VERSION 5.7 ;
  NOWIREEXTENSIONATPIN ON ;
  DIVIDERCHAR "/" ;
  BUSBITCHARS "[]" ;
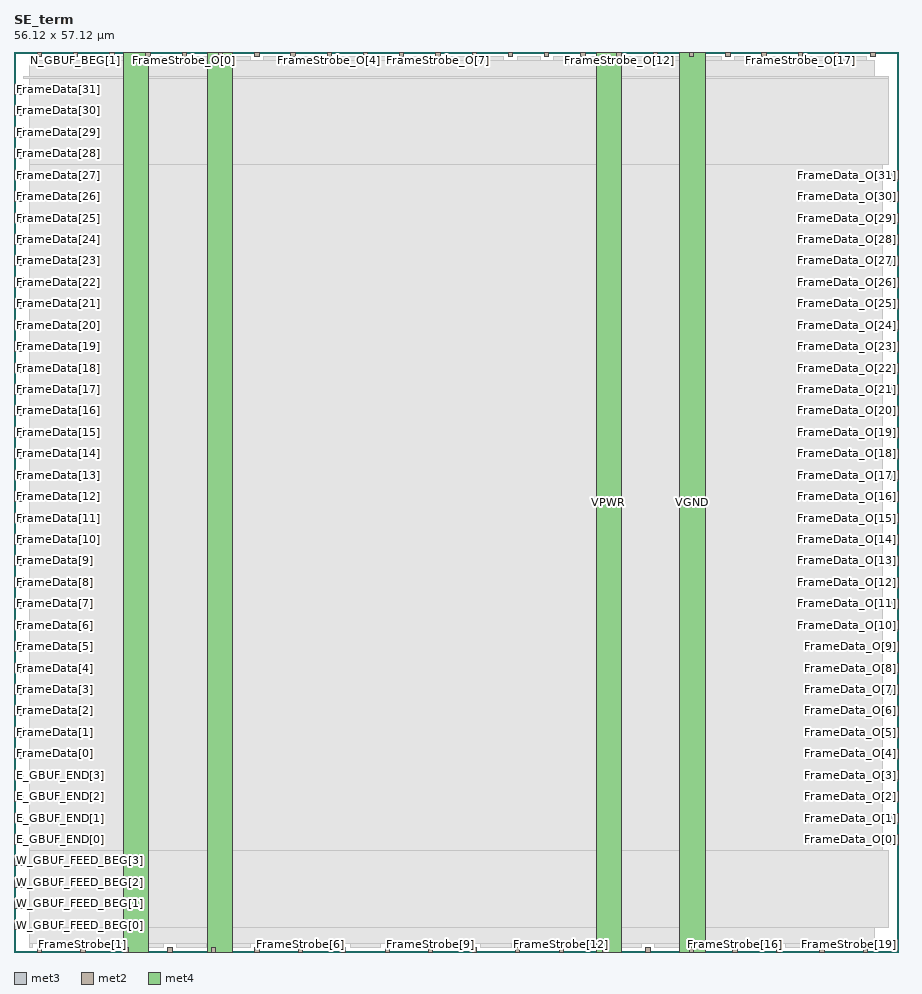
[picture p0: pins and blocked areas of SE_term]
MACRO SE_term
  CLASS BLOCK ;
  FOREIGN SE_term ;
  ORIGIN 0.000 0.000 ;
  SIZE 56.120 BY 57.120 ;
  PIN E_GBUF_END[0]
    DIRECTION INPUT ;
    USE SIGNAL ;
    ANTENNAGATEAREA 0.159000 ;
    PORT
      LAYER met3 ;
        RECT 0.000 6.840 0.600 7.440 ;
    END
  END E_GBUF_END[0]
  PIN E_GBUF_END[1]
    DIRECTION INPUT ;
    USE SIGNAL ;
    ANTENNAGATEAREA 0.159000 ;
    PORT
      LAYER met3 ;
        RECT 0.000 8.200 0.600 8.800 ;
    END
  END E_GBUF_END[1]
  PIN E_GBUF_END[2]
    DIRECTION INPUT ;
    USE SIGNAL ;
    ANTENNAGATEAREA 0.159000 ;
    PORT
      LAYER met3 ;
        RECT 0.000 9.560 0.600 10.160 ;
    END
  END E_GBUF_END[2]
  PIN E_GBUF_END[3]
    DIRECTION INPUT ;
    USE SIGNAL ;
    ANTENNAGATEAREA 0.159000 ;
    PORT
      LAYER met3 ;
        RECT 0.000 10.920 0.600 11.520 ;
    END
  END E_GBUF_END[3]
  PIN FrameData[0]
    DIRECTION INPUT ;
    USE SIGNAL ;
    ANTENNAGATEAREA 0.593700 ;
    ANTENNADIFFAREA 0.434700 ;
    PORT
      LAYER met3 ;
        RECT 0.000 12.280 0.600 12.880 ;
    END
  END FrameData[0]
  PIN FrameData[10]
    DIRECTION INPUT ;
    USE SIGNAL ;
    ANTENNAGATEAREA 0.159000 ;
    PORT
      LAYER met3 ;
        RECT 0.000 25.880 0.600 26.480 ;
    END
  END FrameData[10]
  PIN FrameData[11]
    DIRECTION INPUT ;
    USE SIGNAL ;
    ANTENNAGATEAREA 0.159000 ;
    PORT
      LAYER met3 ;
        RECT 0.000 27.240 0.600 27.840 ;
    END
  END FrameData[11]
  PIN FrameData[12]
    DIRECTION INPUT ;
    USE SIGNAL ;
    ANTENNAGATEAREA 0.159000 ;
    PORT
      LAYER met3 ;
        RECT 0.000 28.600 0.600 29.200 ;
    END
  END FrameData[12]
  PIN FrameData[13]
    DIRECTION INPUT ;
    USE SIGNAL ;
    ANTENNAGATEAREA 0.159000 ;
    PORT
      LAYER met3 ;
        RECT 0.000 29.960 0.600 30.560 ;
    END
  END FrameData[13]
  PIN FrameData[14]
    DIRECTION INPUT ;
    USE SIGNAL ;
    ANTENNAGATEAREA 0.159000 ;
    PORT
      LAYER met3 ;
        RECT 0.000 31.320 0.600 31.920 ;
    END
  END FrameData[14]
  PIN FrameData[15]
    DIRECTION INPUT ;
    USE SIGNAL ;
    ANTENNAGATEAREA 0.159000 ;
    PORT
      LAYER met3 ;
        RECT 0.000 32.680 0.600 33.280 ;
    END
  END FrameData[15]
  PIN FrameData[16]
    DIRECTION INPUT ;
    USE SIGNAL ;
    ANTENNAGATEAREA 0.159000 ;
    PORT
      LAYER met3 ;
        RECT 0.000 34.040 0.600 34.640 ;
    END
  END FrameData[16]
  PIN FrameData[17]
    DIRECTION INPUT ;
    USE SIGNAL ;
    ANTENNAGATEAREA 0.159000 ;
    PORT
      LAYER met3 ;
        RECT 0.000 35.400 0.600 36.000 ;
    END
  END FrameData[17]
  PIN FrameData[18]
    DIRECTION INPUT ;
    USE SIGNAL ;
    ANTENNAGATEAREA 0.593700 ;
    ANTENNADIFFAREA 0.434700 ;
    PORT
      LAYER met3 ;
        RECT 0.000 36.760 0.600 37.360 ;
    END
  END FrameData[18]
  PIN FrameData[19]
    DIRECTION INPUT ;
    USE SIGNAL ;
    ANTENNAGATEAREA 0.159000 ;
    PORT
      LAYER met3 ;
        RECT 0.000 38.120 0.600 38.720 ;
    END
  END FrameData[19]
  PIN FrameData[1]
    DIRECTION INPUT ;
    USE SIGNAL ;
    ANTENNAGATEAREA 0.159000 ;
    PORT
      LAYER met3 ;
        RECT 0.000 13.640 0.600 14.240 ;
    END
  END FrameData[1]
  PIN FrameData[20]
    DIRECTION INPUT ;
    USE SIGNAL ;
    ANTENNAGATEAREA 0.593700 ;
    ANTENNADIFFAREA 0.434700 ;
    PORT
      LAYER met3 ;
        RECT 0.000 39.480 0.600 40.080 ;
    END
  END FrameData[20]
  PIN FrameData[21]
    DIRECTION INPUT ;
    USE SIGNAL ;
    ANTENNAGATEAREA 0.159000 ;
    PORT
      LAYER met3 ;
        RECT 0.000 40.840 0.600 41.440 ;
    END
  END FrameData[21]
  PIN FrameData[22]
    DIRECTION INPUT ;
    USE SIGNAL ;
    ANTENNAGATEAREA 0.159000 ;
    PORT
      LAYER met3 ;
        RECT 0.000 42.200 0.600 42.800 ;
    END
  END FrameData[22]
  PIN FrameData[23]
    DIRECTION INPUT ;
    USE SIGNAL ;
    ANTENNAGATEAREA 0.159000 ;
    PORT
      LAYER met3 ;
        RECT 0.000 43.560 0.600 44.160 ;
    END
  END FrameData[23]
  PIN FrameData[24]
    DIRECTION INPUT ;
    USE SIGNAL ;
    ANTENNAGATEAREA 0.593700 ;
    ANTENNADIFFAREA 0.434700 ;
    PORT
      LAYER met3 ;
        RECT 0.000 44.920 0.600 45.520 ;
    END
  END FrameData[24]
  PIN FrameData[25]
    DIRECTION INPUT ;
    USE SIGNAL ;
    ANTENNAGATEAREA 0.159000 ;
    PORT
      LAYER met3 ;
        RECT 0.000 46.280 0.600 46.880 ;
    END
  END FrameData[25]
  PIN FrameData[26]
    DIRECTION INPUT ;
    USE SIGNAL ;
    ANTENNAGATEAREA 0.593700 ;
    ANTENNADIFFAREA 0.434700 ;
    PORT
      LAYER met3 ;
        RECT 0.000 47.640 0.600 48.240 ;
    END
  END FrameData[26]
  PIN FrameData[27]
    DIRECTION INPUT ;
    USE SIGNAL ;
    ANTENNAGATEAREA 0.159000 ;
    PORT
      LAYER met3 ;
        RECT 0.000 49.000 0.600 49.600 ;
    END
  END FrameData[27]
  PIN FrameData[28]
    DIRECTION INPUT ;
    USE SIGNAL ;
    ANTENNAGATEAREA 0.318000 ;
    PORT
      LAYER met3 ;
        RECT 0.000 50.360 0.600 50.960 ;
    END
  END FrameData[28]
  PIN FrameData[29]
    DIRECTION INPUT ;
    USE SIGNAL ;
    ANTENNAGATEAREA 0.318000 ;
    PORT
      LAYER met3 ;
        RECT 0.000 51.720 0.600 52.320 ;
    END
  END FrameData[29]
  PIN FrameData[2]
    DIRECTION INPUT ;
    USE SIGNAL ;
    ANTENNAGATEAREA 0.159000 ;
    PORT
      LAYER met3 ;
        RECT 0.000 15.000 0.600 15.600 ;
    END
  END FrameData[2]
  PIN FrameData[30]
    DIRECTION INPUT ;
    USE SIGNAL ;
    ANTENNAGATEAREA 0.318000 ;
    PORT
      LAYER met3 ;
        RECT 0.000 53.080 0.600 53.680 ;
    END
  END FrameData[30]
  PIN FrameData[31]
    DIRECTION INPUT ;
    USE SIGNAL ;
    ANTENNAGATEAREA 0.318000 ;
    PORT
      LAYER met3 ;
        RECT 0.000 54.440 0.600 55.040 ;
    END
  END FrameData[31]
  PIN FrameData[3]
    DIRECTION INPUT ;
    USE SIGNAL ;
    ANTENNAGATEAREA 0.159000 ;
    PORT
      LAYER met3 ;
        RECT 0.000 16.360 0.600 16.960 ;
    END
  END FrameData[3]
  PIN FrameData[4]
    DIRECTION INPUT ;
    USE SIGNAL ;
    ANTENNAGATEAREA 0.159000 ;
    PORT
      LAYER met3 ;
        RECT 0.000 17.720 0.600 18.320 ;
    END
  END FrameData[4]
  PIN FrameData[5]
    DIRECTION INPUT ;
    USE SIGNAL ;
    ANTENNAGATEAREA 0.159000 ;
    PORT
      LAYER met3 ;
        RECT 0.000 19.080 0.600 19.680 ;
    END
  END FrameData[5]
  PIN FrameData[6]
    DIRECTION INPUT ;
    USE SIGNAL ;
    ANTENNAGATEAREA 0.593700 ;
    ANTENNADIFFAREA 0.434700 ;
    PORT
      LAYER met3 ;
        RECT 0.000 20.440 0.600 21.040 ;
    END
  END FrameData[6]
  PIN FrameData[7]
    DIRECTION INPUT ;
    USE SIGNAL ;
    ANTENNAGATEAREA 0.159000 ;
    PORT
      LAYER met3 ;
        RECT 0.000 21.800 0.600 22.400 ;
    END
  END FrameData[7]
  PIN FrameData[8]
    DIRECTION INPUT ;
    USE SIGNAL ;
    ANTENNAGATEAREA 0.593700 ;
    ANTENNADIFFAREA 0.434700 ;
    PORT
      LAYER met3 ;
        RECT 0.000 23.160 0.600 23.760 ;
    END
  END FrameData[8]
  PIN FrameData[9]
    DIRECTION INPUT ;
    USE SIGNAL ;
    ANTENNAGATEAREA 0.159000 ;
    PORT
      LAYER met3 ;
        RECT 0.000 24.520 0.600 25.120 ;
    END
  END FrameData[9]
  PIN FrameData_O[0]
    DIRECTION OUTPUT ;
    USE SIGNAL ;
    ANTENNADIFFAREA 0.702900 ;
    PORT
      LAYER met3 ;
        RECT 55.520 6.840 56.120 7.440 ;
    END
  END FrameData_O[0]
  PIN FrameData_O[10]
    DIRECTION OUTPUT ;
    USE SIGNAL ;
    ANTENNADIFFAREA 0.702900 ;
    PORT
      LAYER met3 ;
        RECT 55.520 20.440 56.120 21.040 ;
    END
  END FrameData_O[10]
  PIN FrameData_O[11]
    DIRECTION OUTPUT ;
    USE SIGNAL ;
    ANTENNADIFFAREA 0.702900 ;
    PORT
      LAYER met3 ;
        RECT 55.520 21.800 56.120 22.400 ;
    END
  END FrameData_O[11]
  PIN FrameData_O[12]
    DIRECTION OUTPUT ;
    USE SIGNAL ;
    ANTENNADIFFAREA 0.702900 ;
    PORT
      LAYER met3 ;
        RECT 55.520 23.160 56.120 23.760 ;
    END
  END FrameData_O[12]
  PIN FrameData_O[13]
    DIRECTION OUTPUT ;
    USE SIGNAL ;
    ANTENNADIFFAREA 0.702900 ;
    PORT
      LAYER met3 ;
        RECT 55.520 24.520 56.120 25.120 ;
    END
  END FrameData_O[13]
  PIN FrameData_O[14]
    DIRECTION OUTPUT ;
    USE SIGNAL ;
    ANTENNADIFFAREA 0.702900 ;
    PORT
      LAYER met3 ;
        RECT 55.520 25.880 56.120 26.480 ;
    END
  END FrameData_O[14]
  PIN FrameData_O[15]
    DIRECTION OUTPUT ;
    USE SIGNAL ;
    ANTENNADIFFAREA 0.702900 ;
    PORT
      LAYER met3 ;
        RECT 55.520 27.240 56.120 27.840 ;
    END
  END FrameData_O[15]
  PIN FrameData_O[16]
    DIRECTION OUTPUT ;
    USE SIGNAL ;
    ANTENNADIFFAREA 0.702900 ;
    PORT
      LAYER met3 ;
        RECT 55.520 28.600 56.120 29.200 ;
    END
  END FrameData_O[16]
  PIN FrameData_O[17]
    DIRECTION OUTPUT ;
    USE SIGNAL ;
    ANTENNADIFFAREA 0.702900 ;
    PORT
      LAYER met3 ;
        RECT 55.520 29.960 56.120 30.560 ;
    END
  END FrameData_O[17]
  PIN FrameData_O[18]
    DIRECTION OUTPUT ;
    USE SIGNAL ;
    ANTENNADIFFAREA 0.702900 ;
    PORT
      LAYER met3 ;
        RECT 55.520 31.320 56.120 31.920 ;
    END
  END FrameData_O[18]
  PIN FrameData_O[19]
    DIRECTION OUTPUT ;
    USE SIGNAL ;
    ANTENNADIFFAREA 0.702900 ;
    PORT
      LAYER met3 ;
        RECT 55.520 32.680 56.120 33.280 ;
    END
  END FrameData_O[19]
  PIN FrameData_O[1]
    DIRECTION OUTPUT ;
    USE SIGNAL ;
    ANTENNADIFFAREA 0.702900 ;
    PORT
      LAYER met3 ;
        RECT 55.520 8.200 56.120 8.800 ;
    END
  END FrameData_O[1]
  PIN FrameData_O[20]
    DIRECTION OUTPUT ;
    USE SIGNAL ;
    ANTENNADIFFAREA 0.702900 ;
    PORT
      LAYER met3 ;
        RECT 55.520 34.040 56.120 34.640 ;
    END
  END FrameData_O[20]
  PIN FrameData_O[21]
    DIRECTION OUTPUT ;
    USE SIGNAL ;
    ANTENNADIFFAREA 0.702900 ;
    PORT
      LAYER met3 ;
        RECT 55.520 35.400 56.120 36.000 ;
    END
  END FrameData_O[21]
  PIN FrameData_O[22]
    DIRECTION OUTPUT ;
    USE SIGNAL ;
    ANTENNADIFFAREA 0.702900 ;
    PORT
      LAYER met3 ;
        RECT 55.520 36.760 56.120 37.360 ;
    END
  END FrameData_O[22]
  PIN FrameData_O[23]
    DIRECTION OUTPUT ;
    USE SIGNAL ;
    ANTENNADIFFAREA 0.702900 ;
    PORT
      LAYER met3 ;
        RECT 55.520 38.120 56.120 38.720 ;
    END
  END FrameData_O[23]
  PIN FrameData_O[24]
    DIRECTION OUTPUT ;
    USE SIGNAL ;
    ANTENNADIFFAREA 0.702900 ;
    PORT
      LAYER met3 ;
        RECT 55.520 39.480 56.120 40.080 ;
    END
  END FrameData_O[24]
  PIN FrameData_O[25]
    DIRECTION OUTPUT ;
    USE SIGNAL ;
    ANTENNADIFFAREA 0.702900 ;
    PORT
      LAYER met3 ;
        RECT 55.520 40.840 56.120 41.440 ;
    END
  END FrameData_O[25]
  PIN FrameData_O[26]
    DIRECTION OUTPUT ;
    USE SIGNAL ;
    ANTENNADIFFAREA 0.702900 ;
    PORT
      LAYER met3 ;
        RECT 55.520 42.200 56.120 42.800 ;
    END
  END FrameData_O[26]
  PIN FrameData_O[27]
    DIRECTION OUTPUT ;
    USE SIGNAL ;
    ANTENNADIFFAREA 0.702900 ;
    PORT
      LAYER met3 ;
        RECT 55.520 43.560 56.120 44.160 ;
    END
  END FrameData_O[27]
  PIN FrameData_O[28]
    DIRECTION OUTPUT ;
    USE SIGNAL ;
    ANTENNADIFFAREA 0.702900 ;
    PORT
      LAYER met3 ;
        RECT 55.520 44.920 56.120 45.520 ;
    END
  END FrameData_O[28]
  PIN FrameData_O[29]
    DIRECTION OUTPUT ;
    USE SIGNAL ;
    ANTENNADIFFAREA 0.702900 ;
    PORT
      LAYER met3 ;
        RECT 55.520 46.280 56.120 46.880 ;
    END
  END FrameData_O[29]
  PIN FrameData_O[2]
    DIRECTION OUTPUT ;
    USE SIGNAL ;
    ANTENNADIFFAREA 0.702900 ;
    PORT
      LAYER met3 ;
        RECT 55.520 9.560 56.120 10.160 ;
    END
  END FrameData_O[2]
  PIN FrameData_O[30]
    DIRECTION OUTPUT ;
    USE SIGNAL ;
    ANTENNADIFFAREA 0.702900 ;
    PORT
      LAYER met3 ;
        RECT 55.520 47.640 56.120 48.240 ;
    END
  END FrameData_O[30]
  PIN FrameData_O[31]
    DIRECTION OUTPUT ;
    USE SIGNAL ;
    ANTENNADIFFAREA 0.702900 ;
    PORT
      LAYER met3 ;
        RECT 55.520 49.000 56.120 49.600 ;
    END
  END FrameData_O[31]
  PIN FrameData_O[3]
    DIRECTION OUTPUT ;
    USE SIGNAL ;
    ANTENNADIFFAREA 0.702900 ;
    PORT
      LAYER met3 ;
        RECT 55.520 10.920 56.120 11.520 ;
    END
  END FrameData_O[3]
  PIN FrameData_O[4]
    DIRECTION OUTPUT ;
    USE SIGNAL ;
    ANTENNADIFFAREA 0.702900 ;
    PORT
      LAYER met3 ;
        RECT 55.520 12.280 56.120 12.880 ;
    END
  END FrameData_O[4]
  PIN FrameData_O[5]
    DIRECTION OUTPUT ;
    USE SIGNAL ;
    ANTENNADIFFAREA 0.702900 ;
    PORT
      LAYER met3 ;
        RECT 55.520 13.640 56.120 14.240 ;
    END
  END FrameData_O[5]
  PIN FrameData_O[6]
    DIRECTION OUTPUT ;
    USE SIGNAL ;
    ANTENNADIFFAREA 0.702900 ;
    PORT
      LAYER met3 ;
        RECT 55.520 15.000 56.120 15.600 ;
    END
  END FrameData_O[6]
  PIN FrameData_O[7]
    DIRECTION OUTPUT ;
    USE SIGNAL ;
    ANTENNADIFFAREA 0.702900 ;
    PORT
      LAYER met3 ;
        RECT 55.520 16.360 56.120 16.960 ;
    END
  END FrameData_O[7]
  PIN FrameData_O[8]
    DIRECTION OUTPUT ;
    USE SIGNAL ;
    ANTENNADIFFAREA 0.702900 ;
    PORT
      LAYER met3 ;
        RECT 55.520 17.720 56.120 18.320 ;
    END
  END FrameData_O[8]
  PIN FrameData_O[9]
    DIRECTION OUTPUT ;
    USE SIGNAL ;
    ANTENNADIFFAREA 0.702900 ;
    PORT
      LAYER met3 ;
        RECT 55.520 19.080 56.120 19.680 ;
    END
  END FrameData_O[9]
  PIN FrameStrobe[0]
    DIRECTION INPUT ;
    USE SIGNAL ;
    ANTENNAGATEAREA 0.795000 ;
    PORT
      LAYER met2 ;
        RECT 1.470 0.000 1.750 0.280 ;
    END
  END FrameStrobe[0]
  PIN FrameStrobe[10]
    DIRECTION INPUT ;
    USE SIGNAL ;
    ANTENNAGATEAREA 0.159000 ;
    PORT
      LAYER met2 ;
        RECT 29.070 0.000 29.350 0.280 ;
    END
  END FrameStrobe[10]
  PIN FrameStrobe[11]
    DIRECTION INPUT ;
    USE SIGNAL ;
    ANTENNAGATEAREA 0.159000 ;
    PORT
      LAYER met2 ;
        RECT 31.830 0.000 32.110 0.280 ;
    END
  END FrameStrobe[11]
  PIN FrameStrobe[12]
    DIRECTION INPUT ;
    USE SIGNAL ;
    ANTENNAGATEAREA 0.159000 ;
    PORT
      LAYER met2 ;
        RECT 34.590 0.000 34.870 0.280 ;
    END
  END FrameStrobe[12]
  PIN FrameStrobe[13]
    DIRECTION INPUT ;
    USE SIGNAL ;
    ANTENNAGATEAREA 0.159000 ;
    PORT
      LAYER met2 ;
        RECT 37.350 0.000 37.630 0.280 ;
    END
  END FrameStrobe[13]
  PIN FrameStrobe[14]
    DIRECTION INPUT ;
    USE SIGNAL ;
    ANTENNAGATEAREA 0.159000 ;
    PORT
      LAYER met2 ;
        RECT 40.110 0.000 40.390 0.280 ;
    END
  END FrameStrobe[14]
  PIN FrameStrobe[15]
    DIRECTION INPUT ;
    USE SIGNAL ;
    ANTENNAGATEAREA 0.159000 ;
    PORT
      LAYER met2 ;
        RECT 42.870 0.000 43.150 0.280 ;
    END
  END FrameStrobe[15]
  PIN FrameStrobe[16]
    DIRECTION INPUT ;
    USE SIGNAL ;
    ANTENNAGATEAREA 0.159000 ;
    PORT
      LAYER met2 ;
        RECT 45.630 0.000 45.910 0.280 ;
    END
  END FrameStrobe[16]
  PIN FrameStrobe[17]
    DIRECTION INPUT ;
    USE SIGNAL ;
    ANTENNAGATEAREA 0.159000 ;
    PORT
      LAYER met2 ;
        RECT 48.390 0.000 48.670 0.280 ;
    END
  END FrameStrobe[17]
  PIN FrameStrobe[18]
    DIRECTION INPUT ;
    USE SIGNAL ;
    ANTENNAGATEAREA 0.159000 ;
    PORT
      LAYER met2 ;
        RECT 51.150 0.000 51.430 0.280 ;
    END
  END FrameStrobe[18]
  PIN FrameStrobe[19]
    DIRECTION INPUT ;
    USE SIGNAL ;
    ANTENNAGATEAREA 0.159000 ;
    PORT
      LAYER met2 ;
        RECT 53.910 0.000 54.190 0.280 ;
    END
  END FrameStrobe[19]
  PIN FrameStrobe[1]
    DIRECTION INPUT ;
    USE SIGNAL ;
    ANTENNAGATEAREA 0.159000 ;
    PORT
      LAYER met2 ;
        RECT 4.230 0.000 4.510 0.280 ;
    END
  END FrameStrobe[1]
  PIN FrameStrobe[2]
    DIRECTION INPUT ;
    USE SIGNAL ;
    ANTENNAGATEAREA 0.159000 ;
    PORT
      LAYER met2 ;
        RECT 6.990 0.000 7.270 0.280 ;
    END
  END FrameStrobe[2]
  PIN FrameStrobe[3]
    DIRECTION INPUT ;
    USE SIGNAL ;
    ANTENNAGATEAREA 0.159000 ;
    PORT
      LAYER met2 ;
        RECT 9.750 0.000 10.030 0.280 ;
    END
  END FrameStrobe[3]
  PIN FrameStrobe[4]
    DIRECTION INPUT ;
    USE SIGNAL ;
    ANTENNAGATEAREA 0.159000 ;
    PORT
      LAYER met2 ;
        RECT 12.510 0.000 12.790 0.280 ;
    END
  END FrameStrobe[4]
  PIN FrameStrobe[5]
    DIRECTION INPUT ;
    USE SIGNAL ;
    ANTENNAGATEAREA 0.159000 ;
    PORT
      LAYER met2 ;
        RECT 15.270 0.000 15.550 0.280 ;
    END
  END FrameStrobe[5]
  PIN FrameStrobe[6]
    DIRECTION INPUT ;
    USE SIGNAL ;
    ANTENNAGATEAREA 0.159000 ;
    PORT
      LAYER met2 ;
        RECT 18.030 0.000 18.310 0.280 ;
    END
  END FrameStrobe[6]
  PIN FrameStrobe[7]
    DIRECTION INPUT ;
    USE SIGNAL ;
    ANTENNAGATEAREA 0.159000 ;
    PORT
      LAYER met2 ;
        RECT 20.790 0.000 21.070 0.280 ;
    END
  END FrameStrobe[7]
  PIN FrameStrobe[8]
    DIRECTION INPUT ;
    USE SIGNAL ;
    ANTENNAGATEAREA 0.159000 ;
    PORT
      LAYER met2 ;
        RECT 23.550 0.000 23.830 0.280 ;
    END
  END FrameStrobe[8]
  PIN FrameStrobe[9]
    DIRECTION INPUT ;
    USE SIGNAL ;
    ANTENNAGATEAREA 0.159000 ;
    PORT
      LAYER met2 ;
        RECT 26.310 0.000 26.590 0.280 ;
    END
  END FrameStrobe[9]
  PIN FrameStrobe_O[0]
    DIRECTION OUTPUT ;
    USE SIGNAL ;
    ANTENNADIFFAREA 0.702900 ;
    PORT
      LAYER met2 ;
        RECT 10.670 56.840 10.950 57.120 ;
    END
  END FrameStrobe_O[0]
  PIN FrameStrobe_O[10]
    DIRECTION OUTPUT ;
    USE SIGNAL ;
    ANTENNADIFFAREA 0.702900 ;
    PORT
      LAYER met2 ;
        RECT 33.670 56.840 33.950 57.120 ;
    END
  END FrameStrobe_O[10]
  PIN FrameStrobe_O[11]
    DIRECTION OUTPUT ;
    USE SIGNAL ;
    ANTENNADIFFAREA 0.702900 ;
    PORT
      LAYER met2 ;
        RECT 35.970 56.840 36.250 57.120 ;
    END
  END FrameStrobe_O[11]
  PIN FrameStrobe_O[12]
    DIRECTION OUTPUT ;
    USE SIGNAL ;
    ANTENNADIFFAREA 0.702900 ;
    PORT
      LAYER met2 ;
        RECT 38.270 56.840 38.550 57.120 ;
    END
  END FrameStrobe_O[12]
  PIN FrameStrobe_O[13]
    DIRECTION OUTPUT ;
    USE SIGNAL ;
    ANTENNADIFFAREA 0.702900 ;
    PORT
      LAYER met2 ;
        RECT 40.570 56.840 40.850 57.120 ;
    END
  END FrameStrobe_O[13]
  PIN FrameStrobe_O[14]
    DIRECTION OUTPUT ;
    USE SIGNAL ;
    ANTENNADIFFAREA 0.702900 ;
    PORT
      LAYER met2 ;
        RECT 42.870 56.840 43.150 57.120 ;
    END
  END FrameStrobe_O[14]
  PIN FrameStrobe_O[15]
    DIRECTION OUTPUT ;
    USE SIGNAL ;
    ANTENNADIFFAREA 0.702900 ;
    PORT
      LAYER met2 ;
        RECT 45.170 56.840 45.450 57.120 ;
    END
  END FrameStrobe_O[15]
  PIN FrameStrobe_O[16]
    DIRECTION OUTPUT ;
    USE SIGNAL ;
    ANTENNADIFFAREA 0.702900 ;
    PORT
      LAYER met2 ;
        RECT 47.470 56.840 47.750 57.120 ;
    END
  END FrameStrobe_O[16]
  PIN FrameStrobe_O[17]
    DIRECTION OUTPUT ;
    USE SIGNAL ;
    ANTENNADIFFAREA 0.702900 ;
    PORT
      LAYER met2 ;
        RECT 49.770 56.840 50.050 57.120 ;
    END
  END FrameStrobe_O[17]
  PIN FrameStrobe_O[18]
    DIRECTION OUTPUT ;
    USE SIGNAL ;
    ANTENNADIFFAREA 0.702900 ;
    PORT
      LAYER met2 ;
        RECT 52.070 56.840 52.350 57.120 ;
    END
  END FrameStrobe_O[18]
  PIN FrameStrobe_O[19]
    DIRECTION OUTPUT ;
    USE SIGNAL ;
    ANTENNADIFFAREA 0.702900 ;
    PORT
      LAYER met2 ;
        RECT 54.370 56.840 54.650 57.120 ;
    END
  END FrameStrobe_O[19]
  PIN FrameStrobe_O[1]
    DIRECTION OUTPUT ;
    USE SIGNAL ;
    ANTENNADIFFAREA 0.702900 ;
    PORT
      LAYER met2 ;
        RECT 12.970 56.840 13.250 57.120 ;
    END
  END FrameStrobe_O[1]
  PIN FrameStrobe_O[2]
    DIRECTION OUTPUT ;
    USE SIGNAL ;
    ANTENNADIFFAREA 0.702900 ;
    PORT
      LAYER met2 ;
        RECT 15.270 56.840 15.550 57.120 ;
    END
  END FrameStrobe_O[2]
  PIN FrameStrobe_O[3]
    DIRECTION OUTPUT ;
    USE SIGNAL ;
    ANTENNADIFFAREA 0.702900 ;
    PORT
      LAYER met2 ;
        RECT 17.570 56.840 17.850 57.120 ;
    END
  END FrameStrobe_O[3]
  PIN FrameStrobe_O[4]
    DIRECTION OUTPUT ;
    USE SIGNAL ;
    ANTENNADIFFAREA 0.702900 ;
    PORT
      LAYER met2 ;
        RECT 19.870 56.840 20.150 57.120 ;
    END
  END FrameStrobe_O[4]
  PIN FrameStrobe_O[5]
    DIRECTION OUTPUT ;
    USE SIGNAL ;
    ANTENNADIFFAREA 0.702900 ;
    PORT
      LAYER met2 ;
        RECT 22.170 56.840 22.450 57.120 ;
    END
  END FrameStrobe_O[5]
  PIN FrameStrobe_O[6]
    DIRECTION OUTPUT ;
    USE SIGNAL ;
    ANTENNADIFFAREA 0.702900 ;
    PORT
      LAYER met2 ;
        RECT 24.470 56.840 24.750 57.120 ;
    END
  END FrameStrobe_O[6]
  PIN FrameStrobe_O[7]
    DIRECTION OUTPUT ;
    USE SIGNAL ;
    ANTENNADIFFAREA 0.702900 ;
    PORT
      LAYER met2 ;
        RECT 26.770 56.840 27.050 57.120 ;
    END
  END FrameStrobe_O[7]
  PIN FrameStrobe_O[8]
    DIRECTION OUTPUT ;
    USE SIGNAL ;
    ANTENNADIFFAREA 0.702900 ;
    PORT
      LAYER met2 ;
        RECT 29.070 56.840 29.350 57.120 ;
    END
  END FrameStrobe_O[8]
  PIN FrameStrobe_O[9]
    DIRECTION OUTPUT ;
    USE SIGNAL ;
    ANTENNADIFFAREA 0.702900 ;
    PORT
      LAYER met2 ;
        RECT 31.370 56.840 31.650 57.120 ;
    END
  END FrameStrobe_O[9]
  PIN N_GBUF_BEG[0]
    DIRECTION OUTPUT ;
    USE SIGNAL ;
    ANTENNADIFFAREA 0.702900 ;
    PORT
      LAYER met2 ;
        RECT 1.470 56.840 1.750 57.120 ;
    END
  END N_GBUF_BEG[0]
  PIN N_GBUF_BEG[1]
    DIRECTION OUTPUT ;
    USE SIGNAL ;
    ANTENNADIFFAREA 0.702900 ;
    PORT
      LAYER met2 ;
        RECT 3.770 56.840 4.050 57.120 ;
    END
  END N_GBUF_BEG[1]
  PIN N_GBUF_BEG[2]
    DIRECTION OUTPUT ;
    USE SIGNAL ;
    ANTENNADIFFAREA 0.702900 ;
    PORT
      LAYER met2 ;
        RECT 6.070 56.840 6.350 57.120 ;
    END
  END N_GBUF_BEG[2]
  PIN N_GBUF_BEG[3]
    DIRECTION OUTPUT ;
    USE SIGNAL ;
    ANTENNADIFFAREA 0.702900 ;
    PORT
      LAYER met2 ;
        RECT 8.370 56.840 8.650 57.120 ;
    END
  END N_GBUF_BEG[3]
  PIN VGND
    DIRECTION INOUT ;
    USE GROUND ;
    PORT
      LAYER met4 ;
        RECT 12.260 0.000 13.860 57.120 ;
    END
    PORT
      LAYER met4 ;
        RECT 42.260 0.000 43.860 57.120 ;
    END
  END VGND
  PIN VPWR
    DIRECTION INOUT ;
    USE POWER ;
    PORT
      LAYER met4 ;
        RECT 6.960 0.000 8.560 57.120 ;
    END
    PORT
      LAYER met4 ;
        RECT 36.960 0.000 38.560 57.120 ;
    END
  END VPWR
  PIN W_GBUF_FEED_BEG[0]
    DIRECTION OUTPUT ;
    USE SIGNAL ;
    ANTENNADIFFAREA 0.702900 ;
    PORT
      LAYER met3 ;
        RECT 0.000 1.400 0.600 2.000 ;
    END
  END W_GBUF_FEED_BEG[0]
  PIN W_GBUF_FEED_BEG[1]
    DIRECTION OUTPUT ;
    USE SIGNAL ;
    ANTENNADIFFAREA 0.702900 ;
    PORT
      LAYER met3 ;
        RECT 0.000 2.760 0.600 3.360 ;
    END
  END W_GBUF_FEED_BEG[1]
  PIN W_GBUF_FEED_BEG[2]
    DIRECTION OUTPUT ;
    USE SIGNAL ;
    ANTENNADIFFAREA 0.702900 ;
    PORT
      LAYER met3 ;
        RECT 0.000 4.120 0.600 4.720 ;
    END
  END W_GBUF_FEED_BEG[2]
  PIN W_GBUF_FEED_BEG[3]
    DIRECTION OUTPUT ;
    USE SIGNAL ;
    ANTENNADIFFAREA 0.702900 ;
    PORT
      LAYER met3 ;
        RECT 0.000 5.480 0.600 6.080 ;
    END
  END W_GBUF_FEED_BEG[3]
  OBS
      LAYER nwell ;
        RECT 2.570 2.635 53.550 54.590 ;
      LAYER li1 ;
        RECT 2.760 2.635 53.360 54.485 ;
      LAYER met1 ;
        RECT 0.990 2.480 54.670 54.640 ;
      LAYER met2 ;
        RECT 1.010 56.560 1.190 56.850 ;
        RECT 2.030 56.560 3.490 56.850 ;
        RECT 4.330 56.560 5.790 56.850 ;
        RECT 6.630 56.560 8.090 56.850 ;
        RECT 8.930 56.560 10.390 56.850 ;
        RECT 11.230 56.560 12.690 56.850 ;
        RECT 13.530 56.560 14.990 56.850 ;
        RECT 15.830 56.560 17.290 56.850 ;
        RECT 18.130 56.560 19.590 56.850 ;
        RECT 20.430 56.560 21.890 56.850 ;
        RECT 22.730 56.560 24.190 56.850 ;
        RECT 25.030 56.560 26.490 56.850 ;
        RECT 27.330 56.560 28.790 56.850 ;
        RECT 29.630 56.560 31.090 56.850 ;
        RECT 31.930 56.560 33.390 56.850 ;
        RECT 34.230 56.560 35.690 56.850 ;
        RECT 36.530 56.560 37.990 56.850 ;
        RECT 38.830 56.560 40.290 56.850 ;
        RECT 41.130 56.560 42.590 56.850 ;
        RECT 43.430 56.560 44.890 56.850 ;
        RECT 45.730 56.560 47.190 56.850 ;
        RECT 48.030 56.560 49.490 56.850 ;
        RECT 50.330 56.560 51.790 56.850 ;
        RECT 52.630 56.560 54.090 56.850 ;
        RECT 1.010 0.560 54.640 56.560 ;
        RECT 1.010 0.270 1.190 0.560 ;
        RECT 2.030 0.270 3.950 0.560 ;
        RECT 4.790 0.270 6.710 0.560 ;
        RECT 7.550 0.270 9.470 0.560 ;
        RECT 10.310 0.270 12.230 0.560 ;
        RECT 13.070 0.270 14.990 0.560 ;
        RECT 15.830 0.270 17.750 0.560 ;
        RECT 18.590 0.270 20.510 0.560 ;
        RECT 21.350 0.270 23.270 0.560 ;
        RECT 24.110 0.270 26.030 0.560 ;
        RECT 26.870 0.270 28.790 0.560 ;
        RECT 29.630 0.270 31.550 0.560 ;
        RECT 32.390 0.270 34.310 0.560 ;
        RECT 35.150 0.270 37.070 0.560 ;
        RECT 37.910 0.270 39.830 0.560 ;
        RECT 40.670 0.270 42.590 0.560 ;
        RECT 43.430 0.270 45.350 0.560 ;
        RECT 46.190 0.270 48.110 0.560 ;
        RECT 48.950 0.270 50.870 0.560 ;
        RECT 51.710 0.270 53.630 0.560 ;
        RECT 54.470 0.270 54.640 0.560 ;
      LAYER met3 ;
        RECT 0.600 55.440 55.520 55.585 ;
        RECT 1.000 50.000 55.520 55.440 ;
        RECT 1.000 6.440 55.120 50.000 ;
        RECT 1.000 1.535 55.520 6.440 ;
  END
END SE_term
END LIBRARY

